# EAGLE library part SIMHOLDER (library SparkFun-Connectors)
SIM Cellular Card Socket SMT 6 pin standard connection. SparkFun Products: SIM Socket SparkFun Cellular Shield - MG2639 SparkFun SIM Card Socket Breakout

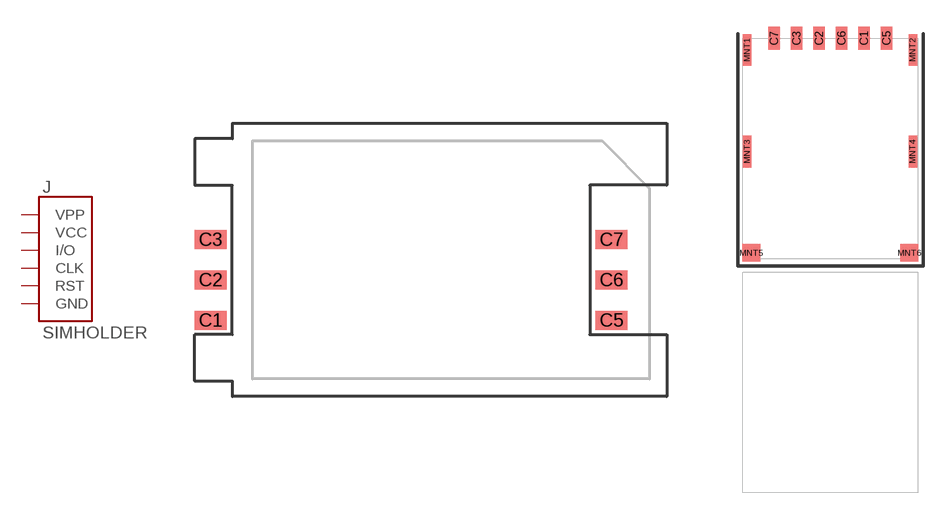
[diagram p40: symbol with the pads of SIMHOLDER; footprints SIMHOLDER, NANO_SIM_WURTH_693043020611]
Designator prefix J

## SIMHOLDERSIM (PROD_ID: CONN-08536; SF_ID: PRT-00548)  [SIMHOLDER]
C1  VCC  pwr
C2  RST  in
C3  CLK  in
C5  GND  pwr
C6  VPP  in
C7  I/O

## SIMHOLDERNANOSIM (PROD_ID: CONN-14097)  [NANO_SIM_WURTH_693043020611]
Pads as for SIMHOLDER

## Footprint SIMHOLDER (pad centres in mm)
SIM Card Socket SMT Specifications: Pin count: 6 Pin pitch:2.54mm Datasheet referenced for footprint Example device(s): SIMHOLDER
smd 2 x 1.2: C1 -12.61,-3.81; C2 -12.61,-1.27; C3 -12.61,1.27; C5 12.61,-3.81; C6 12.61,-1.27; C7 12.61,1.27

## Footprint NANO_SIM_WURTH_693043020611 (pad centres in mm)
Wurth Nano-SIM Holder &ndash; 693043020611 Datasheet
smd 0.65 x 1.3: C1 1.905,6.25; C2 -0.635,6.25; C3 -1.905,6.25; C5 3.175,6.25; C6 0.635,6.25; C7 -3.175,6.25
smd 0.48 x 1.8: MNT1 -4.69,5.58; MNT2 4.66,5.58; MNT3 -4.69,-0.17; MNT4 4.66,-0.17
smd 1.03 x 1: MNT5 -4.465,-5.89; MNT6 4.465,-5.89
